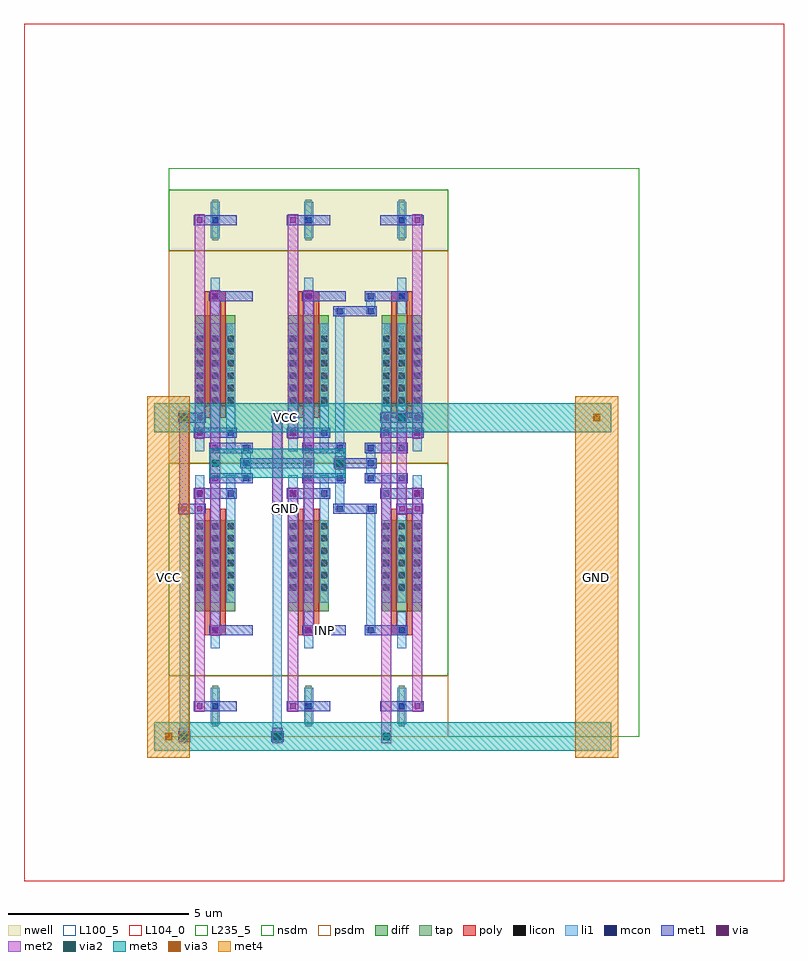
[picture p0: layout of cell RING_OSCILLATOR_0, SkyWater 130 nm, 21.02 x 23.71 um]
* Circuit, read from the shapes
.subckt RING_OSCILLATOR_0 GND INP VCC
XM1 INP n1 GND GND sky130_fd_pr__nfet_01v8 w=2.52 l=0.15 m=2
XM2 n2 INP GND GND sky130_fd_pr__nfet_01v8 w=2.52 l=0.15 m=2
XM3 n1 n2 GND GND sky130_fd_pr__nfet_01v8 w=2.52 l=0.15 m=2
XM4 INP n1 VCC VCC sky130_fd_pr__pfet_01v8 w=2.52 l=0.15 m=2
XM5 n2 INP VCC VCC sky130_fd_pr__pfet_01v8 w=2.52 l=0.15 m=2
XM6 n1 n2 VCC VCC sky130_fd_pr__pfet_01v8 w=2.52 l=0.15 m=2
.ends

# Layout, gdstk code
from math import pi, radians
import gdstk
lib = gdstk.Library(unit=1e-6, precision=1e-09)
def R(c, l, rs):  # rectangles x0, y0, x1, y1
    for r in rs: c.add(gdstk.rectangle(r[:2], r[2:], *l))
def A(c, l, x, y, w, h, nx, ny, dx, dy):  # array of equal rectangles
    R(c, l, [(x+i*dx, y+j*dy, x+i*dx+w, y+j*dy+h) for i in range(nx) for j in range(ny)])
def P(c, l, *ps):  # polygons
    for p in ps: c.add(gdstk.Polygon(p, *l))
nwell = (64, 20)
diff = (65, 20)
tap = (65, 44)
poly = (66, 20)
licon = (66, 44)
li1 = (67, 20)
mcon = (67, 44)
met1 = (68, 20)
via = (68, 44)
met2 = (69, 20)
via2 = (69, 44)
met3 = (70, 20)
via3 = (70, 44)
met4 = (71, 20)
nsdm = (93, 44)
psdm = (94, 20)
L100_5 = (100, 5)
L104_0 = (104, 0)
L235_5 = (235, 5)

nmos_s_94657632_x1_y1_16 = lib.new_cell('NMOS_S_94657632_X1_Y1_1678382966_1678382968')
R(nmos_s_94657632_x1_y1_16, diff, [(0.735,1.575,1.845,4.095)])
R(nmos_s_94657632_x1_y1_16, tap, [(1.205,6.16,1.375,7.28)])
R(nmos_s_94657632_x1_y1_16, poly, [(1,1.26,1.15,4.62), (1.43,1.26,1.58,4.62), (1,4.485,1.58,4.755)])
A(nmos_s_94657632_x1_y1_16, licon, 0.775, 1.655, 0.17, 0.17, 3, 6, 0.43, 0.34)
R(nmos_s_94657632_x1_y1_16, licon, [(1.205,4.535,1.375,4.705), (1.205,6.635,1.375,6.805)])
A(nmos_s_94657632_x1_y1_16, li1, 0.735, 0.335, 0.25, 3.53, 3, 1, 0.43, 0)
R(nmos_s_94657632_x1_y1_16, li1, [(1.165,4.115,1.415,5.125), (1.165,6.215,1.415,7.225)])
R(nmos_s_94657632_x1_y1_16, mcon, [(1.205,0.335,1.375,0.505), (0.775,0.755,0.945,0.925), (1.635,0.755,1.805,0.925), (1.205,4.535,1.375,4.705), (1.205,6.635,1.375,6.805)])
R(nmos_s_94657632_x1_y1_16, met1, [(0.26,0.28,1.46,0.56), (0.69,0.7,1.89,0.98), (0.26,4.48,1.46,4.76), (0.69,6.58,1.89,6.86)])
R(nmos_s_94657632_x1_y1_16, via, [(1.645,0.765,1.795,0.915), (1.645,6.645,1.795,6.795)])
R(nmos_s_94657632_x1_y1_16, met2, [(1.58,0.68,1.86,6.88)])
R(nmos_s_94657632_x1_y1_16, nsdm, [(0,0,2.58,5.88)])
R(nmos_s_94657632_x1_y1_16, psdm, [(0,5.88,2.58,7.56)])
R(nmos_s_94657632_x1_y1_16, L100_5, [(0,0,2.58,7.56)])

pmos_s_13339638_x1_y1_16 = lib.new_cell('PMOS_S_13339638_X1_Y1_1678382967_1678382968')
R(pmos_s_13339638_x1_y1_16, nwell, [(0,0,2.58,7.56)])
R(pmos_s_13339638_x1_y1_16, diff, [(0.735,1.575,1.845,4.095)])
R(pmos_s_13339638_x1_y1_16, tap, [(1.205,6.16,1.375,7.28)])
R(pmos_s_13339638_x1_y1_16, poly, [(1,1.26,1.15,4.62), (1.43,1.26,1.58,4.62), (1,4.485,1.58,4.755)])
A(pmos_s_13339638_x1_y1_16, licon, 0.775, 1.655, 0.17, 0.17, 3, 6, 0.43, 0.34)
R(pmos_s_13339638_x1_y1_16, licon, [(1.205,4.535,1.375,4.705), (1.205,6.635,1.375,6.805)])
A(pmos_s_13339638_x1_y1_16, li1, 0.735, 0.335, 0.25, 3.53, 3, 1, 0.43, 0)
R(pmos_s_13339638_x1_y1_16, li1, [(1.165,4.115,1.415,5.125), (1.165,6.215,1.415,7.225)])
R(pmos_s_13339638_x1_y1_16, mcon, [(1.205,0.335,1.375,0.505), (0.775,0.755,0.945,0.925), (1.635,0.755,1.805,0.925), (1.205,4.535,1.375,4.705), (1.205,6.635,1.375,6.805)])
R(pmos_s_13339638_x1_y1_16, met1, [(0.26,0.28,1.46,0.56), (0.69,0.7,1.89,0.98), (0.26,4.48,1.46,4.76), (0.69,6.58,1.89,6.86)])
R(pmos_s_13339638_x1_y1_16, via, [(1.645,0.765,1.795,0.915), (1.645,6.645,1.795,6.795)])
R(pmos_s_13339638_x1_y1_16, met2, [(1.58,0.68,1.86,6.88)])
R(pmos_s_13339638_x1_y1_16, nsdm, [(0,5.88,2.58,7.56)])
R(pmos_s_13339638_x1_y1_16, psdm, [(0,0,2.58,5.88)])
R(pmos_s_13339638_x1_y1_16, L100_5, [(0,0,2.58,7.56)])

stage2_inv_2455088_pg0_0 = lib.new_cell('STAGE2_INV_2455088_PG0_0_0_1678382968')
R(stage2_inv_2455088_pg0_0, li1, [(2.025,2.855,2.275,3.025), (2.025,2.855,2.275,3.025), (2.025,2.855,2.275,3.025), (2.025,2.855,2.275,3.025), (2.025,2.855,2.275,3.025), (2.025,2.855,2.275,3.025), (2.025,2.94,2.275,6.3), (2.025,6.215,2.275,6.385), (2.025,6.215,2.275,6.385), (2.025,6.215,2.275,6.385), (2.025,6.215,2.275,6.385), (2.025,6.215,2.275,6.385), (2.025,6.215,2.275,6.385), (2.885,6.215,3.135,6.385), (2.885,6.215,3.135,6.385), (2.885,6.215,3.135,6.385), (2.885,6.215,3.135,6.385), (2.885,6.215,3.135,6.385), (2.885,6.215,3.135,6.385), (2.885,6.3,3.135,7.14), (2.025,7.055,2.275,7.225), (2.025,7.055,2.275,7.225), (2.885,7.055,3.135,7.225), (2.885,7.055,3.135,7.225), (2.885,7.055,3.135,7.225), (2.885,7.055,3.135,7.225), (2.885,7.055,3.135,7.225), (2.885,7.055,3.135,7.225), (2.025,7.14,2.275,7.98), (2.885,7.14,3.135,7.98), (2.025,7.895,2.275,8.065), (2.025,7.895,2.275,8.065), (2.885,7.895,3.135,8.065), (2.885,7.895,3.135,8.065), (2.885,7.895,3.135,8.065), (2.885,7.895,3.135,8.065), (2.885,7.98,3.135,11.76), (2.025,11.675,2.275,11.845), (2.025,11.675,2.275,11.845), (2.885,11.675,3.135,11.845), (2.885,11.675,3.135,11.845), (2.025,11.76,2.275,12.18), (2.025,12.095,2.275,12.265), (2.025,12.095,2.275,12.265)])
R(stage2_inv_2455088_pg0_0, mcon, [(2.065,2.855,2.235,3.025), (2.065,2.855,2.235,3.025), (2.065,2.855,2.235,3.025), (2.065,2.855,2.235,3.025), (2.065,2.855,2.235,3.025), (2.065,2.855,2.235,3.025), (2.065,6.215,2.235,6.385), (2.065,6.215,2.235,6.385), (2.065,6.215,2.235,6.385), (2.065,6.215,2.235,6.385), (2.065,6.215,2.235,6.385), (2.065,6.215,2.235,6.385), (2.925,6.215,3.095,6.385), (2.925,6.215,3.095,6.385), (2.925,6.215,3.095,6.385), (2.925,6.215,3.095,6.385), (2.925,6.215,3.095,6.385), (2.925,6.215,3.095,6.385), (2.065,7.055,2.235,7.225), (2.065,7.055,2.235,7.225), (2.925,7.055,3.095,7.225), (2.925,7.055,3.095,7.225), (2.925,7.055,3.095,7.225), (2.925,7.055,3.095,7.225), (2.925,7.055,3.095,7.225), (2.925,7.055,3.095,7.225), (2.065,7.895,2.235,8.065), (2.065,7.895,2.235,8.065), (2.925,7.895,3.095,8.065), (2.925,7.895,3.095,8.065), (2.925,7.895,3.095,8.065), (2.925,7.895,3.095,8.065), (2.065,11.675,2.235,11.845), (2.065,11.675,2.235,11.845), (2.925,11.675,3.095,11.845), (2.925,11.675,3.095,11.845), (2.065,12.095,2.235,12.265), (2.065,12.095,2.235,12.265)])
R(stage2_inv_2455088_pg0_0, met1, [(1.98,2.8,2.32,3.08), (1.98,2.8,2.32,3.08), (1.98,2.8,2.32,3.08), (1.98,2.8,2.32,3.08), (1.98,2.8,2.32,3.08), (1.98,2.8,2.32,3.08), (3.71,2.8,4.03,3.08), (3.71,2.8,4.03,3.08), (1.98,6.16,2.32,6.44), (1.98,6.16,2.32,6.44), (1.98,6.16,2.32,6.44), (1.98,6.16,2.32,6.44), (1.98,6.16,2.32,6.44), (1.98,6.16,2.32,6.44), (2.15,6.16,3.01,6.44), (2.84,6.16,3.18,6.44), (2.84,6.16,3.18,6.44), (2.84,6.16,3.18,6.44), (2.84,6.16,3.18,6.44), (2.84,6.16,3.18,6.44), (2.84,6.16,3.18,6.44), (1.98,7,2.32,7.28), (1.98,7,2.32,7.28), (2.84,7,3.18,7.28), (2.84,7,3.18,7.28), (2.84,7,3.18,7.28), (2.84,7,3.18,7.28), (2.84,7,3.18,7.28), (2.84,7,3.18,7.28), (1.98,7.84,2.32,8.12), (1.98,7.84,2.32,8.12), (2.84,7.84,3.18,8.12), (2.84,7.84,3.18,8.12), (2.84,7.84,3.18,8.12), (2.84,7.84,3.18,8.12), (1.98,11.62,2.32,11.9), (1.98,11.62,2.32,11.9), (2.15,11.62,3.01,11.9), (2.84,11.62,3.18,11.9), (2.84,11.62,3.18,11.9), (1.98,12.04,2.32,12.32), (1.98,12.04,2.32,12.32), (3.71,12.04,4.03,12.32), (3.71,12.04,4.03,12.32)])
P(stage2_inv_2455088_pg0_0, met1, [(0,0),(0,0),(0,0),(0,0)],
  [(0,0),(0,0),(0,0),(0,0)],
  [(0,0),(0,0),(0,0),(0,0)],
  [(0,0),(0,0),(0,0),(0,0)],
  [(0,0),(0,0),(0,0),(0,0)],
  [(0,0),(0,0),(0,0),(0,0)],
  [(0,0),(0,0),(0,0),(0,0)],
  [(0,0),(0,0),(0,0),(0,0)])
R(stage2_inv_2455088_pg0_0, via, [(3.795,2.865,3.945,3.015), (3.795,2.865,3.945,3.015), (3.795,12.105,3.945,12.255), (3.795,12.105,3.945,12.255)])
R(stage2_inv_2455088_pg0_0, met2, [(3.73,2.78,4.01,3.1), (3.73,2.78,4.01,3.1), (3.73,2.94,4.01,12.18), (3.73,12.02,4.01,12.34), (3.73,12.02,4.01,12.34)])
P(stage2_inv_2455088_pg0_0, met2, [(0,0),(0,0),(0,0),(0,0)],
  [(0,0),(0,0),(0,0),(0,0)],
  [(0,0),(0,0),(0,0),(0,0)],
  [(0,0),(0,0),(0,0),(0,0)])
R(stage2_inv_2455088_pg0_0, L235_5, [(0,0,5.16,15.12)])
stage2_inv_2455088_pg0_0.add(gdstk.Reference(nmos_s_94657632_x1_y1_16, (2.58,7.56), x_reflection=True))
stage2_inv_2455088_pg0_0.add(gdstk.Reference(nmos_s_94657632_x1_y1_16, (2.58,7.56), rotation=pi))
stage2_inv_2455088_pg0_0.add(gdstk.Reference(pmos_s_13339638_x1_y1_16, (2.58,7.56)))
stage2_inv_2455088_pg0_0.add(gdstk.Reference(pmos_s_13339638_x1_y1_16, (2.58,7.56), rotation=pi, x_reflection=True))

c_nmos_s_94657632_x1_y1_16 = lib.new_cell('NMOS_S_94657632_X1_Y1_1678382966_1678382967')
R(c_nmos_s_94657632_x1_y1_16, diff, [(0.735,1.575,1.845,4.095)])
R(c_nmos_s_94657632_x1_y1_16, tap, [(1.205,6.16,1.375,7.28)])
R(c_nmos_s_94657632_x1_y1_16, poly, [(1,1.26,1.15,4.62), (1.43,1.26,1.58,4.62), (1,4.485,1.58,4.755)])
A(c_nmos_s_94657632_x1_y1_16, licon, 0.775, 1.655, 0.17, 0.17, 3, 6, 0.43, 0.34)
R(c_nmos_s_94657632_x1_y1_16, licon, [(1.205,4.535,1.375,4.705), (1.205,6.635,1.375,6.805)])
A(c_nmos_s_94657632_x1_y1_16, li1, 0.735, 0.335, 0.25, 3.53, 3, 1, 0.43, 0)
R(c_nmos_s_94657632_x1_y1_16, li1, [(1.165,4.115,1.415,5.125), (1.165,6.215,1.415,7.225)])
R(c_nmos_s_94657632_x1_y1_16, mcon, [(1.205,0.335,1.375,0.505), (0.775,0.755,0.945,0.925), (1.635,0.755,1.805,0.925), (1.205,4.535,1.375,4.705), (1.205,6.635,1.375,6.805)])
R(c_nmos_s_94657632_x1_y1_16, met1, [(0.26,0.28,1.46,0.56), (0.69,0.7,1.89,0.98), (0.26,4.48,1.46,4.76), (0.69,6.58,1.89,6.86)])
R(c_nmos_s_94657632_x1_y1_16, via, [(1.645,0.765,1.795,0.915), (1.645,6.645,1.795,6.795)])
R(c_nmos_s_94657632_x1_y1_16, met2, [(1.58,0.68,1.86,6.88)])
R(c_nmos_s_94657632_x1_y1_16, nsdm, [(0,0,2.58,5.88)])
R(c_nmos_s_94657632_x1_y1_16, psdm, [(0,5.88,2.58,7.56)])
R(c_nmos_s_94657632_x1_y1_16, L100_5, [(0,0,2.58,7.56)])

c_pmos_s_13339638_x1_y1_16 = lib.new_cell('PMOS_S_13339638_X1_Y1_1678382967_1678382967')
R(c_pmos_s_13339638_x1_y1_16, nwell, [(0,0,2.58,7.56)])
R(c_pmos_s_13339638_x1_y1_16, diff, [(0.735,1.575,1.845,4.095)])
R(c_pmos_s_13339638_x1_y1_16, tap, [(1.205,6.16,1.375,7.28)])
R(c_pmos_s_13339638_x1_y1_16, poly, [(1,1.26,1.15,4.62), (1.43,1.26,1.58,4.62), (1,4.485,1.58,4.755)])
A(c_pmos_s_13339638_x1_y1_16, licon, 0.775, 1.655, 0.17, 0.17, 3, 6, 0.43, 0.34)
R(c_pmos_s_13339638_x1_y1_16, licon, [(1.205,4.535,1.375,4.705), (1.205,6.635,1.375,6.805)])
A(c_pmos_s_13339638_x1_y1_16, li1, 0.735, 0.335, 0.25, 3.53, 3, 1, 0.43, 0)
R(c_pmos_s_13339638_x1_y1_16, li1, [(1.165,4.115,1.415,5.125), (1.165,6.215,1.415,7.225)])
R(c_pmos_s_13339638_x1_y1_16, mcon, [(1.205,0.335,1.375,0.505), (0.775,0.755,0.945,0.925), (1.635,0.755,1.805,0.925), (1.205,4.535,1.375,4.705), (1.205,6.635,1.375,6.805)])
R(c_pmos_s_13339638_x1_y1_16, met1, [(0.26,0.28,1.46,0.56), (0.69,0.7,1.89,0.98), (0.26,4.48,1.46,4.76), (0.69,6.58,1.89,6.86)])
R(c_pmos_s_13339638_x1_y1_16, via, [(1.645,0.765,1.795,0.915), (1.645,6.645,1.795,6.795)])
R(c_pmos_s_13339638_x1_y1_16, met2, [(1.58,0.68,1.86,6.88)])
R(c_pmos_s_13339638_x1_y1_16, nsdm, [(0,5.88,2.58,7.56)])
R(c_pmos_s_13339638_x1_y1_16, psdm, [(0,0,2.58,5.88)])
R(c_pmos_s_13339638_x1_y1_16, L100_5, [(0,0,2.58,7.56)])

inv_49597392_pg0_0_0_167 = lib.new_cell('INV_49597392_PG0_0_0_1678382967')
R(inv_49597392_pg0_0_0_167, li1, [(0.305,7.055,0.555,7.225), (0.305,7.055,0.555,7.225), (0.305,7.14,0.555,7.98), (0.305,7.895,0.555,8.065), (0.305,7.895,0.555,8.065)])
R(inv_49597392_pg0_0_0_167, mcon, [(0.345,7.055,0.515,7.225), (0.345,7.055,0.515,7.225), (0.345,7.895,0.515,8.065), (0.345,7.895,0.515,8.065)])
R(inv_49597392_pg0_0_0_167, met1, [(1.13,2.8,1.45,3.08), (1.13,2.8,1.45,3.08), (0.26,7,0.6,7.28), (0.26,7,0.6,7.28), (0.26,7.84,0.6,8.12), (0.26,7.84,0.6,8.12), (1.13,12.04,1.45,12.32), (1.13,12.04,1.45,12.32)])
P(inv_49597392_pg0_0_0_167, met1, [(0,0),(0,0),(0,0),(0,0)],
  [(0,0),(0,0),(0,0),(0,0)],
  [(0,0),(0,0),(0,0),(0,0)],
  [(0,0),(0,0),(0,0),(0,0)])
R(inv_49597392_pg0_0_0_167, via, [(1.215,2.865,1.365,3.015), (1.215,2.865,1.365,3.015), (1.215,12.105,1.365,12.255), (1.215,12.105,1.365,12.255)])
R(inv_49597392_pg0_0_0_167, met2, [(1.15,2.78,1.43,3.1), (1.15,2.78,1.43,3.1), (1.15,2.94,1.43,12.18), (1.15,12.02,1.43,12.34), (1.15,12.02,1.43,12.34)])
P(inv_49597392_pg0_0_0_167, met2, [(0,0),(0,0),(0,0),(0,0)],
  [(0,0),(0,0),(0,0),(0,0)])
R(inv_49597392_pg0_0_0_167, L235_5, [(0,0,2.58,15.12)])
inv_49597392_pg0_0_0_167.add(gdstk.Reference(c_nmos_s_94657632_x1_y1_16, (0,7.56), x_reflection=True))
inv_49597392_pg0_0_0_167.add(gdstk.Reference(c_pmos_s_13339638_x1_y1_16, (0,7.56)))

ring_oscillator_0 = lib.new_cell('RING_OSCILLATOR_0')
R(ring_oscillator_0, li1, [(0.305,-0.085,0.555,0.085), (2.885,-0.085,3.135,0.085), (0.305,0,0.555,8.82), (2.885,0,3.135,8.82), (2.025,7.475,2.275,7.645), (2.025,7.475,2.275,7.645), (5.465,7.475,5.715,7.645), (5.465,7.475,5.715,7.645), (0.305,8.735,0.555,8.905), (0.305,8.735,0.555,8.905), (2.885,8.735,3.135,8.905), (2.885,8.735,3.135,8.905), (2.885,8.735,3.135,8.905), (2.885,8.735,3.135,8.905)])
P(ring_oscillator_0, li1, [(0,0),(0,0),(0,0),(0,0)],
  [(0,0),(0,0),(0,0),(0,0)])
R(ring_oscillator_0, mcon, [(0.345,-0.085,0.515,0.085), (2.925,-0.085,3.095,0.085), (2.065,7.475,2.235,7.645), (2.065,7.475,2.235,7.645), (5.505,7.475,5.675,7.645), (5.505,7.475,5.675,7.645), (0.345,8.735,0.515,8.905), (0.345,8.735,0.515,8.905), (2.925,8.735,3.095,8.905), (2.925,8.735,3.095,8.905), (2.925,8.735,3.095,8.905), (2.925,8.735,3.095,8.905)])
R(ring_oscillator_0, met1, [(0.26,-0.14,0.6,0.14), (0.27,-0.14,0.59,0.14), (0.281,-0.14,0.579,0.14), (2.84,-0.14,3.18,0.14), (2.85,-0.14,3.17,0.14), (2.861,-0.14,3.159,0.14), (0.27,6.16,0.59,6.44), (0.27,6.16,0.59,6.44), (0.43,6.16,0.86,6.44), (0.7,6.16,1.02,6.44), (0.7,6.16,1.02,6.44), (2.85,6.16,3.17,6.44), (2.85,6.16,3.17,6.44), (2.85,6.16,3.17,6.44), (2.85,6.16,3.17,6.44), (3.01,6.16,3.44,6.44), (3.28,6.16,3.6,6.44), (3.28,6.16,3.6,6.44), (3.28,6.16,3.6,6.44), (3.28,6.16,3.6,6.44), (6.29,6.16,6.61,6.44), (6.29,6.16,6.61,6.44), (6.29,6.16,6.61,6.44), (6.45,6.16,6.88,6.44), (6.72,6.16,7.04,6.44), (6.72,6.16,7.04,6.44), (6.72,6.16,7.04,6.44), (1.98,7.42,2.32,7.7), (1.98,7.42,2.32,7.7), (2.15,7.42,3.87,7.7), (3.71,7.42,4.03,7.7), (3.71,7.42,4.03,7.7), (4.57,7.42,4.89,7.7), (4.73,7.42,5.59,7.7), (5.42,7.42,5.76,7.7), (5.42,7.42,5.76,7.7), (0.26,8.68,0.6,8.96), (0.26,8.68,0.6,8.96), (0.43,8.68,0.86,8.96), (0.7,8.68,1.02,8.96), (0.7,8.68,1.02,8.96), (2.84,8.68,3.18,8.96), (2.84,8.68,3.18,8.96), (2.84,8.68,3.18,8.96), (2.84,8.68,3.18,8.96), (3.01,8.68,3.44,8.96), (3.28,8.68,3.6,8.96), (3.28,8.68,3.6,8.96), (3.28,8.68,3.6,8.96), (3.28,8.68,3.6,8.96), (5.86,8.68,6.18,8.96), (5.86,8.68,6.18,8.96), (5.86,8.68,6.18,8.96), (6.02,8.68,6.88,8.96), (6.72,8.68,7.04,8.96), (6.72,8.68,7.04,8.96), (6.72,8.68,7.04,8.96)])
P(ring_oscillator_0, met1, [(0,0),(0,0),(0,0),(0,0)],
  [(0,0),(0,0),(0,0),(0,0)],
  [(0,0),(0,0),(0,0),(0,0)],
  [(0,0),(0,0),(0,0),(0,0)],
  [(0,0),(0,0),(0,0),(0,0)],
  [(0,0),(0,0),(0,0),(0,0)],
  [(0,0),(0,0),(0,0),(0,0)],
  [(0,0),(0,0),(0,0),(0,0)],
  [(0,0),(0,0),(0,0),(0,0)],
  [(0,0),(0,0),(0,0),(0,0)],
  [(0,0),(0,0),(0,0),(0,0)],
  [(0,0),(0,0),(0,0),(0,0)],
  [(0,0),(0,0),(0,0),(0,0)],
  [(0,0),(0,0),(0,0),(0,0)],
  [(0,0),(0,0),(0,0),(0,0)],
  [(0,0),(0,0),(0,0),(0,0)],
  [(0,0),(0,0),(0,0),(0,0)])
R(ring_oscillator_0, via, [(0.355,-0.075,0.505,0.075), (2.935,-0.075,3.085,0.075), (0.355,6.225,0.505,6.375), (0.355,6.225,0.505,6.375), (0.785,6.225,0.935,6.375), (0.785,6.225,0.935,6.375), (2.935,6.225,3.085,6.375), (2.935,6.225,3.085,6.375), (2.935,6.225,3.085,6.375), (2.935,6.225,3.085,6.375), (3.365,6.225,3.515,6.375), (3.365,6.225,3.515,6.375), (3.365,6.225,3.515,6.375), (3.365,6.225,3.515,6.375), (6.375,6.225,6.525,6.375), (6.375,6.225,6.525,6.375), (6.375,6.225,6.525,6.375), (6.805,6.225,6.955,6.375), (6.805,6.225,6.955,6.375), (6.805,6.225,6.955,6.375), (3.795,7.485,3.945,7.635), (3.795,7.485,3.945,7.635), (4.655,7.485,4.805,7.635), (0.785,8.745,0.935,8.895), (0.785,8.745,0.935,8.895), (3.365,8.745,3.515,8.895), (3.365,8.745,3.515,8.895), (3.365,8.745,3.515,8.895), (3.365,8.745,3.515,8.895), (5.945,8.745,6.095,8.895), (5.945,8.745,6.095,8.895), (5.945,8.745,6.095,8.895), (6.805,8.745,6.955,8.895), (6.805,8.745,6.955,8.895), (6.805,8.745,6.955,8.895)])
R(ring_oscillator_0, met2, [(0.29,-0.185,0.57,0.185), (0.29,-0.185,0.57,0.185), (2.87,-0.185,3.15,0.185), (2.87,-0.185,3.15,0.185), (2.87,-0.185,3.15,0.185), (2.87,-0.185,3.15,0.185), (5.88,-0.185,6.16,0.185), (5.88,-0.185,6.16,0.185), (5.88,-0.185,6.16,0.185), (0.29,-0.16,0.57,0.16), (2.87,-0.16,3.15,0.16), (0.29,0,0.57,0.242), (2.87,0,3.15,0.242), (5.88,0,6.16,8.82), (0.29,6.14,0.57,6.46), (0.29,6.14,0.57,6.46), (0.72,6.14,1,6.46), (0.72,6.14,1,6.46), (2.87,6.14,3.15,6.46), (2.87,6.14,3.15,6.46), (2.87,6.14,3.15,6.46), (2.87,6.14,3.15,6.46), (3.3,6.14,3.58,6.46), (3.3,6.14,3.58,6.46), (3.3,6.14,3.58,6.46), (3.3,6.14,3.58,6.46), (6.31,6.14,6.59,6.46), (6.31,6.14,6.59,6.46), (6.31,6.14,6.59,6.46), (6.74,6.14,7.02,6.46), (6.74,6.14,7.02,6.46), (6.74,6.14,7.02,6.46), (0.29,6.3,0.57,8.82), (2.87,6.3,3.15,8.82), (6.31,6.3,6.59,8.82), (1.15,7.375,1.43,7.745), (1.15,7.375,1.43,7.745), (4.59,7.375,4.87,7.745), (3.73,7.4,4.01,7.72), (3.73,7.4,4.01,7.72), (4.59,7.4,4.87,7.72), (4.59,7.439,4.87,7.681), (0.29,8.635,0.57,9.005), (0.29,8.635,0.57,9.005), (2.87,8.635,3.15,9.005), (2.87,8.635,3.15,9.005), (2.87,8.635,3.15,9.005), (2.87,8.635,3.15,9.005), (6.31,8.635,6.59,9.005), (6.31,8.635,6.59,9.005), (6.31,8.635,6.59,9.005), (0.72,8.66,1,8.98), (0.72,8.66,1,8.98), (3.3,8.66,3.58,8.98), (3.3,8.66,3.58,8.98), (3.3,8.66,3.58,8.98), (3.3,8.66,3.58,8.98), (5.88,8.66,6.16,8.98), (5.88,8.66,6.16,8.98), (5.88,8.66,6.16,8.98), (6.74,8.66,7.02,8.98), (6.74,8.66,7.02,8.98), (6.74,8.66,7.02,8.98)])
P(ring_oscillator_0, met2, [(0,0),(0,0),(0,0),(0,0)],
  [(0,0),(0,0),(0,0),(0,0)])
R(ring_oscillator_0, via2, [(0.33,-0.1,0.53,0.1), (0.33,-0.1,0.53,0.1), (2.91,-0.1,3.11,0.1), (2.91,-0.1,3.11,0.1), (2.91,-0.1,3.11,0.1), (2.91,-0.1,3.11,0.1), (5.92,-0.1,6.12,0.1), (5.92,-0.1,6.12,0.1), (5.92,-0.1,6.12,0.1), (1.19,7.46,1.39,7.66), (1.19,7.46,1.39,7.66), (4.63,7.46,4.83,7.66), (0.33,8.72,0.53,8.92), (0.33,8.72,0.53,8.92), (2.91,8.72,3.11,8.92), (2.91,8.72,3.11,8.92), (2.91,8.72,3.11,8.92), (2.91,8.72,3.11,8.92), (6.35,8.72,6.55,8.92), (6.35,8.72,6.55,8.92), (6.35,8.72,6.55,8.92)])
A(ring_oscillator_0, met3, -0.4, -0.4, 4.24, 0.8, 3, 2, 3.44, 8.82)
R(ring_oscillator_0, met3, [(-0.165,-0.4,0.165,0.4), (0.265,-0.4,0.595,0.4), (0.265,-0.4,0.595,0.4), (2.845,-0.4,3.175,0.4), (2.845,-0.4,3.175,0.4), (2.845,-0.4,3.175,0.4), (2.845,-0.4,3.175,0.4), (5.855,-0.4,6.185,0.4), (5.855,-0.4,6.185,0.4), (5.855,-0.4,6.185,0.4), (9.92,-0.4,12.24,0.4), (1.125,7.16,1.455,7.96), (1.125,7.16,1.455,7.96), (1.29,7.16,4.73,7.96), (4.565,7.16,4.895,7.96), (0.265,8.42,0.595,9.22), (0.265,8.42,0.595,9.22), (2.845,8.42,3.175,9.22), (2.845,8.42,3.175,9.22), (2.845,8.42,3.175,9.22), (2.845,8.42,3.175,9.22), (6.285,8.42,6.615,9.22), (6.285,8.42,6.615,9.22), (6.285,8.42,6.615,9.22), (9.92,8.42,12.24,9.22), (11.675,8.42,12.005,9.22)])
R(ring_oscillator_0, via3, [(-0.1,-0.1,0.1,0.1), (11.74,8.72,11.94,8.92)])
R(ring_oscillator_0, met4, [(-0.59,-0.59,0.59,9.41), (11.25,-0.59,12.43,9.41), (-0.59,-0.165,0.59,0.165), (11.25,8.655,12.43,8.985)])
R(ring_oscillator_0, L104_0, [(-4,-4,17.02,19.71)])
R(ring_oscillator_0, L235_5, [(0,0,13.02,15.71)])
ring_oscillator_0.add(gdstk.Reference(stage2_inv_2455088_pg0_0, (7.74,0), rotation=pi, x_reflection=True))
ring_oscillator_0.add(gdstk.Reference(inv_49597392_pg0_0_0_167, (2.58,0), rotation=pi, x_reflection=True))
ring_oscillator_0.add(gdstk.Label('INP', (4.3,2.94), layer=68, texttype=5))
ring_oscillator_0.add(gdstk.Label('GND', (11.84,4.41), layer=71, texttype=5))
ring_oscillator_0.add(gdstk.Label('GND', (3.225,6.3), layer=68, texttype=5))
ring_oscillator_0.add(gdstk.Label('GND', (11.84,4.41), layer=71, texttype=5))
ring_oscillator_0.add(gdstk.Label('GND', (11.84,4.41), layer=71, texttype=5))
ring_oscillator_0.add(gdstk.Label('GND', (11.84,4.41), layer=71, texttype=5))
ring_oscillator_0.add(gdstk.Label('GND', (11.84,4.41), layer=71, texttype=5))
ring_oscillator_0.add(gdstk.Label('GND', (11.84,4.41), layer=71, texttype=5))
ring_oscillator_0.add(gdstk.Label('GND', (11.84,4.41), layer=71, texttype=5))
ring_oscillator_0.add(gdstk.Label('GND', (11.84,4.41), layer=71, texttype=5))
ring_oscillator_0.add(gdstk.Label('GND', (11.84,4.41), layer=71, texttype=5))
ring_oscillator_0.add(gdstk.Label('GND', (11.84,4.41), layer=71, texttype=5))
ring_oscillator_0.add(gdstk.Label('GND', (11.84,4.41), layer=71, texttype=5))
ring_oscillator_0.add(gdstk.Label('GND', (11.84,4.41), layer=71, texttype=5))
ring_oscillator_0.add(gdstk.Label('VCC', (0,4.41), layer=71, texttype=5))
ring_oscillator_0.add(gdstk.Label('VCC', (3.225,8.82), layer=68, texttype=5))
ring_oscillator_0.add(gdstk.Label('VCC', (0,4.41), layer=71, texttype=5))
ring_oscillator_0.add(gdstk.Label('VCC', (0,4.41), layer=71, texttype=5))
ring_oscillator_0.add(gdstk.Label('VCC', (0,4.41), layer=71, texttype=5))
ring_oscillator_0.add(gdstk.Label('VCC', (0,4.41), layer=71, texttype=5))
ring_oscillator_0.add(gdstk.Label('VCC', (0,4.41), layer=71, texttype=5))
ring_oscillator_0.add(gdstk.Label('VCC', (0,4.41), layer=71, texttype=5))
ring_oscillator_0.add(gdstk.Label('VCC', (0,4.41), layer=71, texttype=5))
ring_oscillator_0.add(gdstk.Label('VCC', (0,4.41), layer=71, texttype=5))
ring_oscillator_0.add(gdstk.Label('VCC', (0,4.41), layer=71, texttype=5))
ring_oscillator_0.add(gdstk.Label('VCC', (0,4.41), layer=71, texttype=5))
ring_oscillator_0.add(gdstk.Label('VCC', (0,4.41), layer=71, texttype=5))
ring_oscillator_0.add(gdstk.Label('VCC', (0,4.41), layer=71, texttype=5))
ring_oscillator_0.add(gdstk.Label('VCC', (0,4.41), layer=71, texttype=5))
ring_oscillator_0.add(gdstk.Label('VCC', (0,4.41), layer=71, texttype=5))
ring_oscillator_0.add(gdstk.Label('VCC', (0,4.41), layer=71, texttype=5))

lib.write_gds('RING_OSCILLATOR_0.gds')
